One B-rep face of a CAD part: STEP entity #11160.
In plain terms, the planar face has unit normal (0, 1, 0).
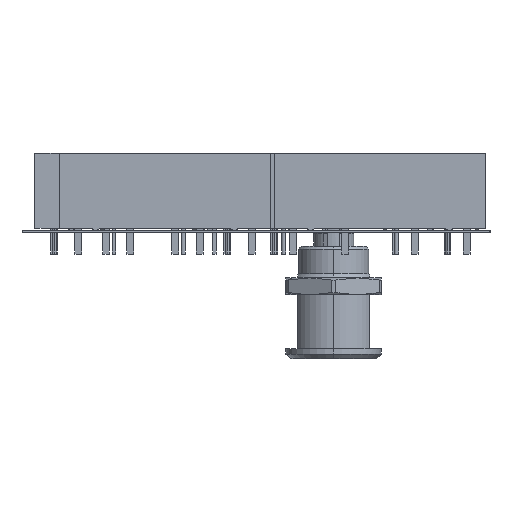
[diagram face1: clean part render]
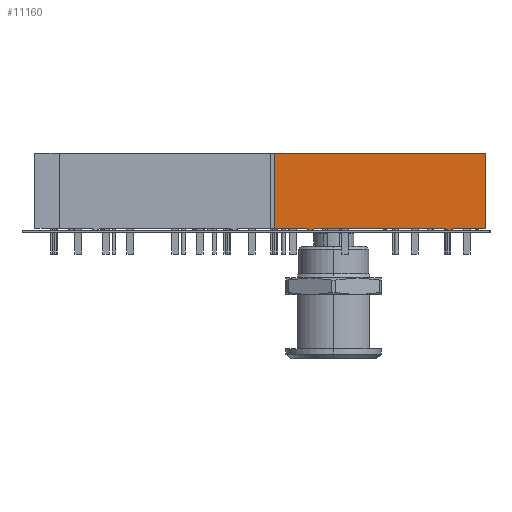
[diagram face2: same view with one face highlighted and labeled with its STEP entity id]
Its self-contained STEP definition (entity closure, numbers rounded to 3 decimals):
#9172 = EDGE_CURVE('',#9173,#9175,#9177,.T.);
#9173 = VERTEX_POINT('',#9174);
#9174 = CARTESIAN_POINT('',(15.5,7.,11.3));
#9175 = VERTEX_POINT('',#9176);
#9176 = CARTESIAN_POINT('',(-15.5,7.,11.3));
#9177 = LINE('',#9178,#9179);
#9178 = CARTESIAN_POINT('',(-15.5,7.,11.3));
#9179 = VECTOR('',#9180,1.);
#9180 = DIRECTION('',(-1.,0.,0.));
#10805 = VERTEX_POINT('',#10806);
#10806 = CARTESIAN_POINT('',(-15.5,7.,0.3));
#10812 = EDGE_CURVE('',#10805,#10813,#10815,.T.);
#10813 = VERTEX_POINT('',#10814);
#10814 = CARTESIAN_POINT('',(-10.774,7.,0.3));
#10815 = LINE('',#10816,#10817);
#10816 = CARTESIAN_POINT('',(-15.5,7.,0.3));
#10817 = VECTOR('',#10818,1.);
#10818 = DIRECTION('',(1.,0.,0.));
#10837 = VERTEX_POINT('',#10838);
#10838 = CARTESIAN_POINT('',(-9.526,7.,0.3));
#10844 = EDGE_CURVE('',#10837,#10845,#10847,.T.);
#10845 = VERTEX_POINT('',#10846);
#10846 = CARTESIAN_POINT('',(9.526,7.,0.3));
#10847 = LINE('',#10848,#10849);
#10848 = CARTESIAN_POINT('',(-9.526,7.,0.3));
#10849 = VECTOR('',#10850,1.);
#10850 = DIRECTION('',(1.,0.,0.));
#10869 = VERTEX_POINT('',#10870);
#10870 = CARTESIAN_POINT('',(10.774,7.,0.3));
#10876 = EDGE_CURVE('',#10869,#10877,#10879,.T.);
#10877 = VERTEX_POINT('',#10878);
#10878 = CARTESIAN_POINT('',(15.5,7.,0.3));
#10879 = LINE('',#10880,#10881);
#10880 = CARTESIAN_POINT('',(10.774,7.,0.3));
#10881 = VECTOR('',#10882,1.);
#10882 = DIRECTION('',(1.,0.,0.));
#11016 = EDGE_CURVE('',#10813,#10837,#11017,.T.);
#11017 = CIRCLE('',#11018,0.8);
#11018 = AXIS2_PLACEMENT_3D('',#11019,#11020,#11021);
#11019 = CARTESIAN_POINT('',(-10.15,7.,0.8));
#11020 = DIRECTION('',(0.,-1.,0.));
#11021 = DIRECTION('',(1.,0.,0.));
#11064 = EDGE_CURVE('',#10845,#10869,#11065,.T.);
#11065 = CIRCLE('',#11066,0.8);
#11066 = AXIS2_PLACEMENT_3D('',#11067,#11068,#11069);
#11067 = CARTESIAN_POINT('',(10.15,7.,0.8));
#11068 = DIRECTION('',(0.,-1.,0.));
#11069 = DIRECTION('',(1.,0.,0.));
#11104 = EDGE_CURVE('',#9175,#10805,#11105,.T.);
#11105 = LINE('',#11106,#11107);
#11106 = CARTESIAN_POINT('',(-15.5,7.,11.3));
#11107 = VECTOR('',#11108,1.);
#11108 = DIRECTION('',(0.,0.,-1.));
#11126 = EDGE_CURVE('',#10877,#9173,#11127,.T.);
#11127 = LINE('',#11128,#11129);
#11128 = CARTESIAN_POINT('',(15.5,7.,11.3));
#11129 = VECTOR('',#11130,1.);
#11130 = DIRECTION('',(0.,0.,1.));
#11160 = ADVANCED_FACE('',(#11161),#11171,.F.);
#11161 = FACE_BOUND('',#11162,.T.);
#11162 = EDGE_LOOP('',(#11163,#11164,#11165,#11166,#11167,#11168,#11169,
    #11170));
#11163 = ORIENTED_EDGE('',*,*,#11104,.F.);
#11164 = ORIENTED_EDGE('',*,*,#9172,.F.);
#11165 = ORIENTED_EDGE('',*,*,#11126,.F.);
#11166 = ORIENTED_EDGE('',*,*,#10876,.F.);
#11167 = ORIENTED_EDGE('',*,*,#11064,.F.);
#11168 = ORIENTED_EDGE('',*,*,#10844,.F.);
#11169 = ORIENTED_EDGE('',*,*,#11016,.F.);
#11170 = ORIENTED_EDGE('',*,*,#10812,.F.);
#11171 = PLANE('',#11172);
#11172 = AXIS2_PLACEMENT_3D('',#11173,#11174,#11175);
#11173 = CARTESIAN_POINT('',(-10.15,7.,0.8));
#11174 = DIRECTION('',(0.,-1.,0.));
#11175 = DIRECTION('',(1.,0.,0.));
